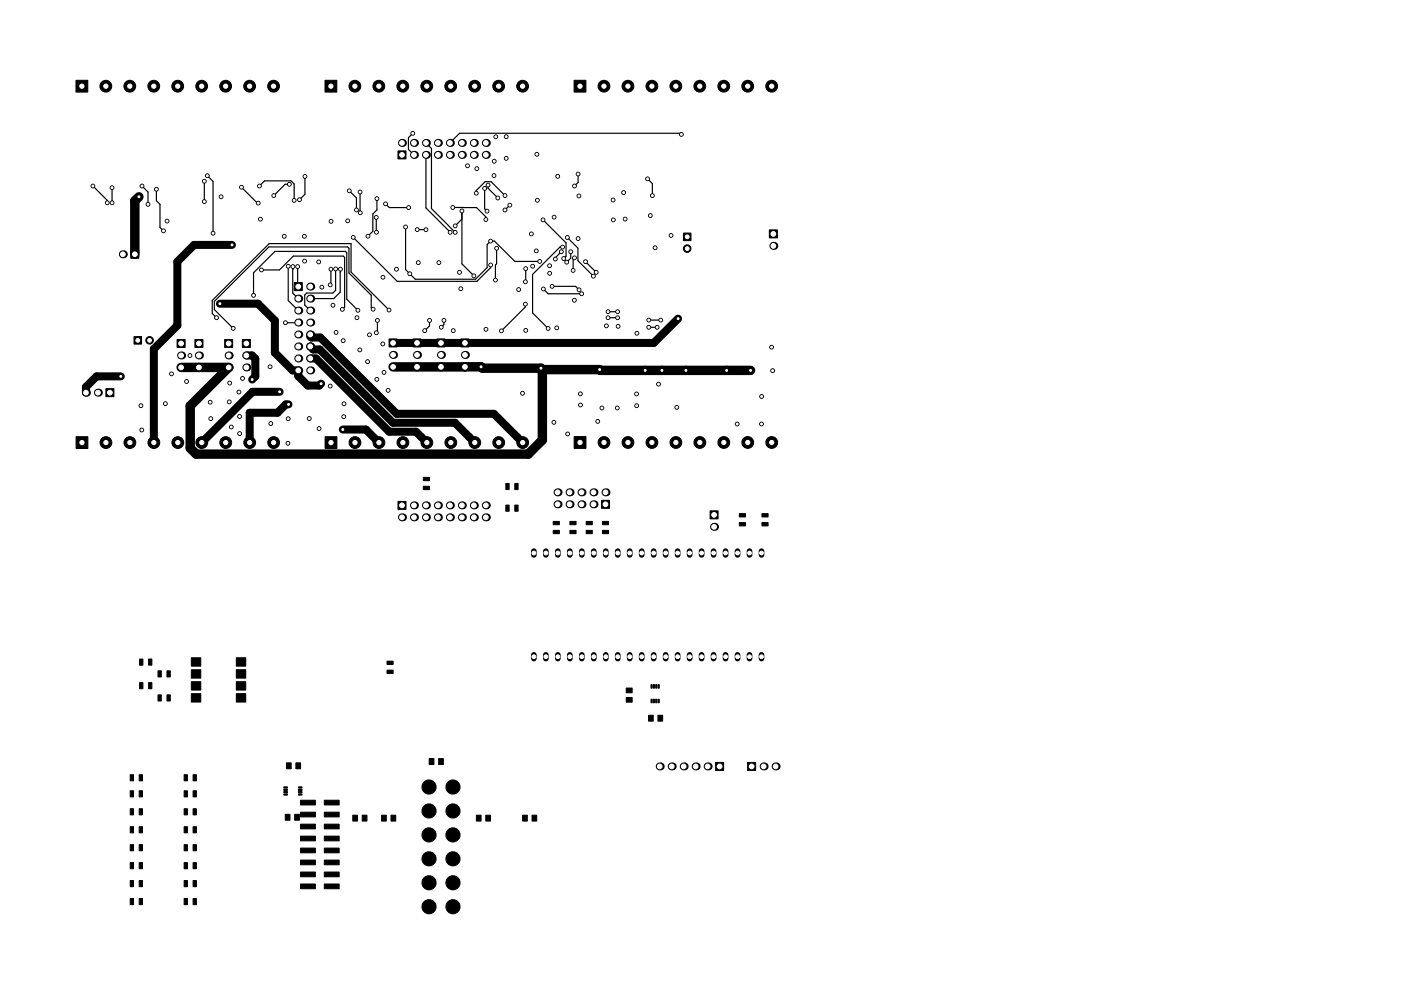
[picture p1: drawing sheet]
<svg xmlns="http://www.w3.org/2000/svg" width="297mm" height="210mm" viewBox="0 0 297 210" stroke-linecap="round" stroke-linejoin="round" font-family="sans-serif">
<g fill="none" stroke="#000" stroke-width="1.2">
<path d="M113.2 116.9v.8M115.7 116.9v.8M118.3 116.9v.8M120.8 116.9v.8M123.4 116.9v.8M125.9 116.9v.8M128.4 116.9v.8M131 116.9v.8M133.5 116.9v.8M136.1 116.9v.8M138.6 116.9v.8M141.1 116.9v.8"/>
<path d="M143.7 116.9v.8M146.2 116.9v.8M148.8 116.9v.8M151.3 116.9v.8M153.8 116.9v.8M156.4 116.9v.8M158.9 116.9v.8M161.5 116.9v.8M113.2 138.9v.8M115.7 138.9v.8M118.3 138.9v.8M120.8 138.9v.8"/>
<path d="M123.4 138.9v.8M125.9 138.9v.8M128.4 138.9v.8M131 138.9v.8M133.5 138.9v.8M136.1 138.9v.8M138.6 138.9v.8M141.1 138.9v.8M143.7 138.9v.8M146.2 138.9v.8M148.8 138.9v.8M151.3 138.9v.8"/>
<path d="M153.8 138.9v.8M156.4 138.9v.8M158.9 138.9v.8M161.5 138.9v.8"/>
</g>
<g fill="#000" stroke="#000" stroke-width=".21">
<path d="M16.1 17h2.5v2.5h-2.5zM68.9 17h2.5v2.5h-2.5zM121.7 17h2.5v2.5h-2.5zM84.4 32h1.7v1.7h-1.7zM27.7 53.1h1.7v1.7h-1.7zM144.9 49.4h1.6v1.6h-1.6zM163.1 48.8h1.7v1.7h-1.7zM28.4 71.4h1.6v1.6h-1.6zM37.5 72h1.7v1.7h-1.7zM41.3 72h1.7v1.7h-1.7zM47.6 72h1.7v1.7h-1.7zM51.4 72h1.7v1.7h-1.7z"/>
<path d="M62.4 60h1.7v1.7h-1.7zM82.5 71.9h1.7v1.7h-1.7zM87.6 71.9h1.7v1.7h-1.7zM92.6 71.9h1.7v1.7h-1.7zM97.7 71.9h1.7v1.7h-1.7zM16.1 92.6h2.5v2.5h-2.5zM22.4 82.5h1.7v1.7h-1.7zM68.9 92.6h2.5v2.5h-2.5zM121.7 92.6h2.5v2.5h-2.5zM84.4 106.4h1.7v1.7h-1.7zM89.7 101.3h1.4v.7h-1.4zM89.7 103.2h1.4v.7h-1.4z"/>
<path d="M107.2 102.6h.7v1.3h-.7zM107.2 107.2h.7v1.3h-.7zM109.1 102.6h.7v1.3h-.7zM109.1 107.2h.7v1.3h-.7zM117.3 110.6h1.3v.7h-1.3zM117.3 112.5h1.3v.7h-1.3zM120.8 112.5h1.3v.7h-1.3zM120.8 110.6h1.3v.7h-1.3zM124.3 110.6h1.3v.7h-1.3zM124.3 112.5h1.3v.7h-1.3zM127.7 110.6h1.3v.7h-1.3zM127.7 112.5h1.3v.7h-1.3z"/>
<path d="M127.5 106.1h1.7v1.7h-1.7zM150.6 108.4h1.6v1.7h-1.6zM156.8 109h1.2v.7h-1.2zM156.8 110.9h1.2v.7h-1.2zM161.6 110.9h1.3v.7h-1.3zM161.6 109h1.3v.7h-1.3zM40.6 139.6h2v1.7h-2zM50.1 139.6h2v1.7h-2zM29.6 139.8h.7v1.3h-.7zM29.6 144.8h.7v1.3h-.7zM31.5 139.8h.7v1.3h-.7zM31.5 144.8h.7v1.3h-.7z"/>
<path d="M33.5 142.3h.7v1.3h-.7zM33.5 147.4h.7v1.3h-.7zM35.4 142.3h.7v1.3h-.7zM35.4 147.4h.7v1.3h-.7zM40.6 142.1h2v1.8h-2zM40.6 144.6h2v1.8h-2zM40.6 147.2h2v1.8h-2zM50.1 147.2h2v1.8h-2zM50.1 144.6h2v1.8h-2zM50.1 142.1h2v1.8h-2zM82 140.3h1.4v.7h-1.4zM82 142.2h1.4v.7h-1.4z"/>
<path d="M132.8 146h1.2v1h-1.2zM132.8 148h1.2v1h-1.2zM137.5 151.8h1v1.2h-1zM138 148.4h.3v.7h-.3zM138 145.3h.3v.7h-.3zM138.5 148.4h.3v.7h-.3zM138.5 145.3h.3v.7h-.3zM139 148.4h.3v.7h-.3zM139 145.3h.3v.7h-.3zM139.5 151.8h1v1.2h-1zM139.5 148.4h.3v.7h-.3zM139.5 145.3h.3v.7h-.3z"/>
<path d="M27.6 164.4h.7v1.3h-.7zM27.6 175.4h.7v1.3h-.7zM27.6 171.6h.7v1.3h-.7zM27.6 167.8h.7v1.3h-.7zM27.6 179.2h.7v1.3h-.7zM29.5 164.4h.7v1.3h-.7zM29.5 175.4h.7v1.3h-.7zM29.5 171.6h.7v1.3h-.7zM29.5 167.8h.7v1.3h-.7zM29.5 179.2h.7v1.3h-.7zM39 179.2h.7v1.3h-.7zM39 171.6h.7v1.3h-.7z"/>
<path d="M39 167.8h.7v1.3h-.7zM39 164.4h.7v1.3h-.7zM39 175.4h.7v1.3h-.7zM40.9 179.2h.7v1.3h-.7zM40.9 171.6h.7v1.3h-.7zM40.9 167.8h.7v1.3h-.7zM40.9 164.4h.7v1.3h-.7zM40.9 175.4h.7v1.3h-.7zM60.2 166.9h.7v.3h-.7zM60.2 167.4h.7v.3h-.7zM60.2 167.9h.7v.3h-.7zM60.2 168.4h.7v.3h-.7z"/>
<path d="M60.5 172.8h1v1.2h-1zM60.7 161.9h1v1.2h-1zM62.5 172.8h1v1.2h-1zM62.7 161.9h1v1.2h-1zM63.3 168.4h.7v.3h-.7zM63.3 167.9h.7v.3h-.7zM63.3 167.4h.7v.3h-.7zM63.3 166.9h.7v.3h-.7zM63.7 169.8h3.2v1h-3.2zM63.7 172.3h3.2v1h-3.2zM63.7 174.9h3.2v1h-3.2zM63.7 177.4h3.2v1h-3.2z"/>
<path d="M63.7 179.9h3.2v1h-3.2zM68.8 169.8h3.1v1h-3.1zM68.8 172.3h3.1v1h-3.1zM68.8 174.9h3.1v1h-3.1zM68.8 177.4h3.1v1h-3.1zM68.8 179.9h3.1v1h-3.1zM74.8 173h1v1.2h-1zM76.8 173h1v1.2h-1zM80.9 173h1v1.2h-1zM82.9 173h1v1.2h-1zM91 161h1v1.2h-1zM93 161h1v1.2h-1z"/>
<path d="M101 173h1v1.2h-1zM103 173h1v1.2h-1zM110.8 173h1v1.2h-1zM112.8 173h1v1.2h-1zM151.7 161.8h1.7v1.7h-1.7zM158.5 161.8h1.7v1.7h-1.7zM27.6 190.6h.7v1.3h-.7zM27.6 186.8h.7v1.3h-.7zM27.6 183h.7v1.3h-.7zM29.5 190.6h.7v1.3h-.7zM29.5 186.8h.7v1.3h-.7zM29.5 183h.7v1.3h-.7z"/>
<path d="M39 190.6h.7v1.3h-.7zM39 186.8h.7v1.3h-.7zM39 183h.7v1.3h-.7zM40.9 190.6h.7v1.3h-.7zM40.9 186.8h.7v1.3h-.7zM40.9 183h.7v1.3h-.7zM63.7 182.5h3.2v1h-3.2zM63.7 185h3.2v1h-3.2zM63.7 187.6h3.2v1h-3.2zM68.8 182.5h3.1v1h-3.1zM68.8 185h3.1v1h-3.1zM68.8 187.6h3.1v1h-3.1z"/>
<circle cx="22.4" cy="18.3" r="1.25"/>
<circle cx="27.5" cy="18.3" r="1.25"/>
<circle cx="32.6" cy="18.3" r="1.25"/>
<circle cx="37.7" cy="18.3" r="1.25"/>
<circle cx="42.8" cy="18.3" r="1.25"/>
<circle cx="47.8" cy="18.3" r="1.25"/>
<circle cx="52.9" cy="18.3" r="1.25"/>
<circle cx="58" cy="18.3" r="1.25"/>
<circle cx="75.2" cy="18.3" r="1.25"/>
<circle cx="80.3" cy="18.3" r="1.25"/>
<circle cx="85.4" cy="18.3" r="1.25"/>
<circle cx="90.5" cy="18.3" r="1.25"/>
<circle cx="95.6" cy="18.3" r="1.25"/>
<circle cx="100.6" cy="18.3" r="1.25"/>
<circle cx="105.7" cy="18.3" r="1.25"/>
<circle cx="110.8" cy="18.3" r="1.25"/>
<circle cx="128.1" cy="18.3" r="1.25"/>
<circle cx="133.1" cy="18.3" r="1.25"/>
<circle cx="138.2" cy="18.3" r="1.25"/>
<circle cx="143.3" cy="18.3" r="1.25"/>
<circle cx="148.4" cy="18.3" r="1.25"/>
<circle cx="153.5" cy="18.3" r="1.25"/>
<circle cx="158.5" cy="18.3" r="1.25"/>
<circle cx="163.6" cy="18.3" r="1.25"/>
<circle cx="19.7" cy="39.5" r=".4"/>
<circle cx="23.8" cy="39.8" r=".4"/>
<circle cx="30.1" cy="39.5" r=".4"/>
<circle cx="43.3" cy="38.5" r=".4"/>
<circle cx="44" cy="37.3" r=".4"/>
<circle cx="51.2" cy="39.7" r=".4"/>
<circle cx="55" cy="39.5" r=".4"/>
<circle cx="61.4" cy="39.1" r=".4"/>
<circle cx="64.7" cy="37.4" r=".4"/>
<circle cx="87.5" cy="28.3" r=".4"/>
<circle cx="99.1" cy="35.2" r=".4"/>
<circle cx="101.1" cy="35.8" r=".4"/>
<circle cx="102.8" cy="40" r=".4"/>
<circle cx="103.5" cy="39.3" r=".4"/>
<circle cx="104.7" cy="37.3" r=".4"/>
<circle cx="104.8" cy="34.2" r=".4"/>
<circle cx="105.1" cy="29" r=".4"/>
<circle cx="107.3" cy="33.6" r=".4"/>
<circle cx="107.3" cy="29" r=".4"/>
<circle cx="113.8" cy="32.7" r=".4"/>
<circle cx="118.2" cy="37.4" r=".4"/>
<circle cx="121.8" cy="39.5" r=".4"/>
<circle cx="122.6" cy="36.9" r=".4"/>
<circle cx="137.3" cy="37.9" r=".4"/>
<circle cx="144.5" cy="28.5" r=".4"/>
<circle cx="22.7" cy="43" r=".4"/>
<circle cx="23.8" cy="43" r=".4"/>
<circle cx="29.5" cy="41.8" r=".4"/>
<circle cx="31.4" cy="43.4" r=".4"/>
<circle cx="33.2" cy="40.2" r=".4"/>
<circle cx="34.7" cy="49" r=".4"/>
<circle cx="35.4" cy="46.9" r=".4"/>
<circle cx="43.3" cy="42.8" r=".4"/>
<circle cx="45.2" cy="49.5" r=".4"/>
<circle cx="46.9" cy="41.8" r=".4"/>
<circle cx="49.2" cy="52" r=".4"/>
<circle cx="54.7" cy="43.1" r=".4"/>
<circle cx="55.2" cy="46.5" r=".4"/>
<circle cx="55.4" cy="57.3" r=".4"/>
<circle cx="58.1" cy="41.5" r=".4"/>
<circle cx="60.3" cy="50.1" r=".4"/>
<circle cx="61.1" cy="56.5" r=".4"/>
<circle cx="62.1" cy="56.6" r=".4"/>
<circle cx="62.4" cy="42.5" r=".4"/>
<circle cx="63.1" cy="56.6" r=".4"/>
<circle cx="63.5" cy="42.4" r=".4"/>
<circle cx="64.5" cy="50.1" r=".4"/>
<circle cx="64.6" cy="55.4" r=".4"/>
<circle cx="67.6" cy="55.6" r=".4"/>
<circle cx="70.2" cy="57.1" r=".4"/>
<circle cx="70.2" cy="47" r=".4"/>
<circle cx="71.2" cy="57.1" r=".4"/>
<circle cx="72.2" cy="57.1" r=".4"/>
<circle cx="73.7" cy="46.9" r=".4"/>
<circle cx="74.1" cy="40.5" r=".4"/>
<circle cx="74.9" cy="50.4" r=".4"/>
<circle cx="75.6" cy="44.5" r=".4"/>
<circle cx="76.3" cy="40.7" r=".4"/>
<circle cx="76.4" cy="45.1" r=".4"/>
<circle cx="78" cy="50.1" r=".4"/>
<circle cx="79.8" cy="46.1" r=".4"/>
<circle cx="79.8" cy="49.3" r=".4"/>
<circle cx="79.9" cy="42.1" r=".4"/>
<circle cx="81.2" cy="58.8" r=".4"/>
<circle cx="81.7" cy="43.3" r=".4"/>
<circle cx="84.1" cy="57.1" r=".4"/>
<circle cx="86" cy="48.2" r=".4"/>
<circle cx="86.6" cy="44" r=".4"/>
<circle cx="86.9" cy="58.1" r=".4"/>
<circle cx="88.5" cy="48.7" r=".4"/>
<circle cx="88.7" cy="55.7" r=".4"/>
<circle cx="90.3" cy="48.7" r=".4"/>
<circle cx="93.1" cy="55.7" r=".4"/>
<circle cx="95.4" cy="49.3" r=".4"/>
<circle cx="96" cy="44" r=".4"/>
<circle cx="96.5" cy="49.3" r=".4"/>
<circle cx="96.5" cy="47.9" r=".4"/>
<circle cx="97.4" cy="57.8" r=".4"/>
<circle cx="97.9" cy="44.7" r=".4"/>
<circle cx="100.5" cy="58.5" r=".4"/>
<circle cx="101" cy="41" r=".4"/>
<circle cx="103" cy="46.6" r=".4"/>
<circle cx="103.3" cy="44.8" r=".4"/>
<circle cx="104" cy="51.2" r=".4"/>
<circle cx="104" cy="56.2" r=".4"/>
<circle cx="105" cy="59.4" r=".4"/>
<circle cx="105.3" cy="52.7" r=".4"/>
<circle cx="105.5" cy="42" r=".4"/>
<circle cx="107.1" cy="44.6" r=".4"/>
<circle cx="107.1" cy="41.5" r=".4"/>
<circle cx="108.1" cy="43.5" r=".4"/>
<circle cx="111.4" cy="59.8" r=".4"/>
<circle cx="111.5" cy="57" r=".4"/>
<circle cx="112.7" cy="49.6" r=".4"/>
<circle cx="112.9" cy="56.5" r=".4"/>
<circle cx="113.7" cy="53.2" r=".4"/>
<circle cx="113.9" cy="42.5" r=".4"/>
<circle cx="114.4" cy="55.5" r=".4"/>
<circle cx="115.1" cy="46.6" r=".4"/>
<circle cx="116.5" cy="56.4" r=".4"/>
<circle cx="116.5" cy="58" r=".4"/>
<circle cx="117.5" cy="46.1" r=".4"/>
<circle cx="117.7" cy="55" r=".4"/>
<circle cx="119" cy="53.4" r=".4"/>
<circle cx="119.3" cy="52.4" r=".4"/>
<circle cx="119.5" cy="54.9" r=".4"/>
<circle cx="120.2" cy="55.6" r=".4"/>
<circle cx="120.3" cy="50.4" r=".4"/>
<circle cx="121" cy="53.4" r=".4"/>
<circle cx="121.5" cy="57.4" r=".4"/>
<circle cx="121.8" cy="54.7" r=".4"/>
<circle cx="122.6" cy="50.6" r=".4"/>
<circle cx="122.7" cy="41.6" r=".4"/>
<circle cx="124.1" cy="55.5" r=".4"/>
<circle cx="125.8" cy="58.6" r=".4"/>
<circle cx="126.4" cy="57.8" r=".4"/>
<circle cx="130" cy="42.4" r=".4"/>
<circle cx="130" cy="46.7" r=".4"/>
<circle cx="132.2" cy="40.9" r=".4"/>
<circle cx="132.5" cy="46.5" r=".4"/>
<circle cx="137.9" cy="45.7" r=".4"/>
<circle cx="138.3" cy="41.5" r=".4"/>
<circle cx="138.9" cy="52.6" r=".4"/>
<circle cx="142.3" cy="50" r=".4"/>
<circle cx="145.7" cy="52.7" r=".8"/>
<circle cx="25.6" cy="79.9" r=".4"/>
<circle cx="31.7" cy="72.2" r=".8"/>
<circle cx="36.4" cy="79.3" r=".4"/>
<circle cx="40.3" cy="75.4" r=".4"/>
<circle cx="45.9" cy="67.4" r=".4"/>
<circle cx="46.6" cy="64.4" r=".4"/>
<circle cx="49.4" cy="69.7" r=".4"/>
<circle cx="53.8" cy="62.7" r=".4"/>
<circle cx="57.3" cy="77.8" r=".4"/>
<circle cx="60.5" cy="68.5" r=".4"/>
<circle cx="68.2" cy="60.9" r=".4"/>
<circle cx="70" cy="60.4" r=".4"/>
<circle cx="70.6" cy="64.8" r=".4"/>
<circle cx="71.3" cy="70.5" r=".4"/>
<circle cx="72.6" cy="65.6" r=".4"/>
<circle cx="72.8" cy="72.3" r=".4"/>
<circle cx="75.7" cy="67.4" r=".4"/>
<circle cx="75.9" cy="65.8" r=".4"/>
<circle cx="76.3" cy="74.2" r=".4"/>
<circle cx="77.9" cy="76.7" r=".4"/>
<circle cx="78.3" cy="71" r=".4"/>
<circle cx="79.1" cy="65.6" r=".4"/>
<circle cx="79.8" cy="70.6" r=".4"/>
<circle cx="80" cy="68" r=".4"/>
<circle cx="81.2" cy="73" r=".4"/>
<circle cx="81.4" cy="79" r=".4"/>
<circle cx="82.5" cy="65.8" r=".4"/>
<circle cx="90.1" cy="70.2" r=".4"/>
<circle cx="91.1" cy="68" r=".4"/>
<circle cx="93.6" cy="69.4" r=".4"/>
<circle cx="94.1" cy="68" r=".4"/>
<circle cx="96.1" cy="70.1" r=".4"/>
<circle cx="97.7" cy="61.3" r=".4"/>
<circle cx="102" cy="77.8" r=".4"/>
<circle cx="103" cy="69.9" r=".4"/>
<circle cx="106.3" cy="70.2" r=".4"/>
<circle cx="110" cy="61.4" r=".4"/>
<circle cx="111.4" cy="64.5" r=".4"/>
<circle cx="111.5" cy="70.1" r=".4"/>
<circle cx="114.7" cy="78.1" r=".4"/>
<circle cx="115.2" cy="61.3" r=".4"/>
<circle cx="116.2" cy="69.7" r=".4"/>
<circle cx="117.1" cy="60.8" r=".4"/>
<circle cx="118" cy="69.6" r=".4"/>
<circle cx="121.8" cy="63.7" r=".4"/>
<circle cx="122.8" cy="61.5" r=".4"/>
<circle cx="123.3" cy="62.3" r=".4"/>
<circle cx="127.1" cy="78.4" r=".4"/>
<circle cx="128.6" cy="69.1" r=".4"/>
<circle cx="128.9" cy="67.4" r=".4"/>
<circle cx="128.9" cy="66.1" r=".4"/>
<circle cx="130.9" cy="66.1" r=".4"/>
<circle cx="130.9" cy="67.4" r=".4"/>
<circle cx="131" cy="69.2" r=".4"/>
<circle cx="135" cy="70.7" r=".4"/>
<circle cx="136.8" cy="78.6" r=".4"/>
<circle cx="137.6" cy="69.4" r=".4"/>
<circle cx="137.6" cy="67.9" r=".4"/>
<circle cx="139.3" cy="69.4" r=".4"/>
<circle cx="140.1" cy="67.9" r=".4"/>
<circle cx="140.3" cy="78.6" r=".4"/>
<circle cx="143.8" cy="67.6" r=".4"/>
<circle cx="145.4" cy="78.6" r=".4"/>
<circle cx="154.1" cy="78.6" r=".4"/>
<circle cx="159.1" cy="78.6" r=".4"/>
<circle cx="163.6" cy="73.7" r=".4"/>
<circle cx="163.8" cy="78.6" r=".4"/>
<circle cx="22.5" cy="93.9" r="1.25"/>
<circle cx="27.5" cy="93.9" r="1.25"/>
<circle cx="29.9" cy="86.1" r=".4"/>
<circle cx="30.1" cy="91.2" r=".4"/>
<circle cx="32.6" cy="93.9" r="1.25"/>
<circle cx="35.1" cy="85.6" r=".4"/>
<circle cx="37.7" cy="93.9" r="1.25"/>
<circle cx="39.6" cy="80.9" r=".4"/>
<circle cx="42.8" cy="93.9" r="1.25"/>
<circle cx="44.6" cy="85.3" r=".4"/>
<circle cx="44.7" cy="88.8" r=".4"/>
<circle cx="47.9" cy="93.9" r="1.25"/>
<circle cx="48.6" cy="85.3" r=".4"/>
<circle cx="48.7" cy="81.3" r=".4"/>
<circle cx="49" cy="90.6" r=".4"/>
<circle cx="50.7" cy="83.2" r=".4"/>
<circle cx="50.8" cy="88.4" r=".4"/>
<circle cx="50.8" cy="92" r=".4"/>
<circle cx="51.4" cy="80.3" r=".4"/>
<circle cx="52.9" cy="93.9" r="1.25"/>
<circle cx="53.5" cy="80.5" r=".4"/>
<circle cx="57.4" cy="89.9" r=".4"/>
<circle cx="58" cy="93.9" r="1.25"/>
<circle cx="59.3" cy="83.1" r=".4"/>
<circle cx="61" cy="94.1" r=".4"/>
<circle cx="61.1" cy="88.8" r=".4"/>
<circle cx="61.2" cy="85.8" r=".4"/>
<circle cx="65.6" cy="88.8" r=".4"/>
<circle cx="67.7" cy="90.9" r=".4"/>
<circle cx="68.1" cy="81.4" r=".4"/>
<circle cx="70" cy="81.9" r=".4"/>
<circle cx="72.7" cy="91.1" r=".4"/>
<circle cx="72.9" cy="88.4" r=".4"/>
<circle cx="72.9" cy="85.7" r=".4"/>
<circle cx="75.3" cy="93.9" r="1.25"/>
<circle cx="79.9" cy="80.5" r=".4"/>
<circle cx="80.3" cy="93.9" r="1.25"/>
<circle cx="82.3" cy="82.8" r=".4"/>
<circle cx="85.4" cy="93.9" r="1.25"/>
<circle cx="90.5" cy="93.9" r="1.25"/>
<circle cx="95.6" cy="93.9" r="1.25"/>
<circle cx="100.7" cy="93.9" r="1.25"/>
<circle cx="105.7" cy="93.9" r="1.25"/>
<circle cx="110.8" cy="83.4" r=".4"/>
<circle cx="110.8" cy="93.9" r="1.25"/>
<circle cx="117.4" cy="89.6" r=".4"/>
<circle cx="120.4" cy="92.1" r=".4"/>
<circle cx="123" cy="83.6" r=".4"/>
<circle cx="123.1" cy="85.9" r=".4"/>
<circle cx="126.7" cy="89.4" r=".4"/>
<circle cx="127.6" cy="86.6" r=".4"/>
<circle cx="128.1" cy="93.9" r="1.25"/>
<circle cx="130.9" cy="86.6" r=".4"/>
<circle cx="133.1" cy="93.9" r="1.25"/>
<circle cx="135" cy="83.6" r=".4"/>
<circle cx="135" cy="86.1" r=".4"/>
<circle cx="138.2" cy="93.9" r="1.25"/>
<circle cx="139.6" cy="81.5" r=".4"/>
<circle cx="143.3" cy="93.9" r="1.25"/>
<circle cx="143.5" cy="86.4" r=".4"/>
<circle cx="148.4" cy="93.9" r="1.25"/>
<circle cx="153.5" cy="93.9" r="1.25"/>
<circle cx="156.3" cy="90" r=".4"/>
<circle cx="158.5" cy="93.9" r="1.25"/>
<circle cx="161.5" cy="90" r=".4"/>
<circle cx="161.5" cy="84.1" r=".4"/>
<circle cx="163.6" cy="93.9" r="1.25"/>
<circle cx="91" cy="177.1" r="1.5"/>
<circle cx="91" cy="172.1" r="1.5"/>
<circle cx="91" cy="167" r="1.5"/>
<circle cx="96" cy="172.1" r="1.5"/>
<circle cx="96" cy="177.1" r="1.5"/>
<circle cx="96" cy="167" r="1.5"/>
<circle cx="91" cy="182.2" r="1.5"/>
<circle cx="91" cy="192.4" r="1.5"/>
<circle cx="91" cy="187.3" r="1.5"/>
<circle cx="96" cy="182.2" r="1.5"/>
<circle cx="96" cy="192.4" r="1.5"/>
<circle cx="96" cy="187.3" r="1.5"/>
</g>
<g fill="#000">
<circle cx="85.2" cy="30.3" r=".85"/>
<circle cx="87.8" cy="30.3" r=".85"/>
<circle cx="87.8" cy="32.9" r=".85"/>
<circle cx="90.3" cy="30.3" r=".85"/>
<circle cx="90.3" cy="32.9" r=".85"/>
<circle cx="92.8" cy="30.3" r=".85"/>
<circle cx="92.8" cy="32.9" r=".85"/>
<circle cx="95.4" cy="32.9" r=".85"/>
<circle cx="95.4" cy="30.3" r=".85"/>
<circle cx="97.9" cy="32.9" r=".85"/>
<circle cx="97.9" cy="30.3" r=".85"/>
<circle cx="100.5" cy="32.9" r=".85"/>
<circle cx="100.5" cy="30.3" r=".85"/>
<circle cx="103" cy="30.3" r=".85"/>
<circle cx="103" cy="32.9" r=".85"/>
<circle cx="26" cy="53.9" r=".85"/>
<circle cx="164" cy="52.2" r=".85"/>
<circle cx="38.4" cy="75.4" r=".85"/>
<circle cx="38.4" cy="78" r=".85"/>
<circle cx="42.2" cy="75.4" r=".85"/>
<circle cx="42.2" cy="78" r=".85"/>
<circle cx="48.5" cy="75.4" r=".85"/>
<circle cx="48.5" cy="78" r=".85"/>
<circle cx="52.2" cy="75.4" r=".85"/>
<circle cx="52.2" cy="78" r=".85"/>
<circle cx="63.2" cy="71" r=".85"/>
<circle cx="63.2" cy="65.9" r=".85"/>
<circle cx="63.2" cy="68.4" r=".85"/>
<circle cx="63.2" cy="73.5" r=".85"/>
<circle cx="63.2" cy="78.6" r=".85"/>
<circle cx="63.2" cy="76" r=".85"/>
<circle cx="63.2" cy="63.3" r=".85"/>
<circle cx="65.8" cy="71" r=".85"/>
<circle cx="65.8" cy="73.5" r=".85"/>
<circle cx="65.8" cy="60.8" r=".85"/>
<circle cx="65.8" cy="63.3" r=".85"/>
<circle cx="65.8" cy="68.4" r=".85"/>
<circle cx="65.8" cy="78.6" r=".85"/>
<circle cx="65.8" cy="65.9" r=".85"/>
<circle cx="65.8" cy="76" r=".85"/>
<circle cx="83.3" cy="75.3" r=".85"/>
<circle cx="83.3" cy="77.8" r=".85"/>
<circle cx="88.4" cy="75.3" r=".85"/>
<circle cx="88.4" cy="77.8" r=".85"/>
<circle cx="93.5" cy="77.8" r=".85"/>
<circle cx="93.5" cy="75.3" r=".85"/>
<circle cx="98.6" cy="77.8" r=".85"/>
<circle cx="98.6" cy="75.3" r=".85"/>
<circle cx="18.2" cy="83.3" r=".85"/>
<circle cx="20.8" cy="83.3" r=".85"/>
<circle cx="85.2" cy="109.8" r=".85"/>
<circle cx="87.8" cy="109.8" r=".85"/>
<circle cx="87.8" cy="107.2" r=".85"/>
<circle cx="90.3" cy="109.8" r=".85"/>
<circle cx="90.3" cy="107.2" r=".85"/>
<circle cx="92.8" cy="109.8" r=".85"/>
<circle cx="92.8" cy="107.2" r=".85"/>
<circle cx="95.4" cy="109.8" r=".85"/>
<circle cx="95.4" cy="107.2" r=".85"/>
<circle cx="97.9" cy="109.8" r=".85"/>
<circle cx="97.9" cy="107.2" r=".85"/>
<circle cx="100.5" cy="107.2" r=".85"/>
<circle cx="100.5" cy="109.8" r=".85"/>
<circle cx="103" cy="109.8" r=".85"/>
<circle cx="103" cy="107.2" r=".85"/>
<circle cx="118.2" cy="107" r=".85"/>
<circle cx="118.2" cy="104.5" r=".85"/>
<circle cx="120.8" cy="104.5" r=".85"/>
<circle cx="120.8" cy="107" r=".85"/>
<circle cx="123.3" cy="104.5" r=".85"/>
<circle cx="123.3" cy="107" r=".85"/>
<circle cx="125.8" cy="107" r=".85"/>
<circle cx="125.8" cy="104.5" r=".85"/>
<circle cx="128.4" cy="104.5" r=".85"/>
<circle cx="151.4" cy="111.8" r=".85"/>
<circle cx="139.9" cy="162.6" r=".85"/>
<circle cx="142.4" cy="162.6" r=".85"/>
<circle cx="145" cy="162.6" r=".85"/>
<circle cx="147.5" cy="162.6" r=".85"/>
<circle cx="150" cy="162.6" r=".85"/>
<circle cx="161.9" cy="162.6" r=".85"/>
<circle cx="164.4" cy="162.6" r=".85"/>
</g>
<path d="M29.5 41.8l-.9 .8v11.3M38.4 78h10.1l-8.2 8.1v9l1.3 1.2h70.4l3-2.9v-15M83.3 77.8h18.7l.3 .3h12.4l.3 .3M115 78.4h12.1l.2 .2h31.8" fill="none" stroke="#000" stroke-width="2"/>
<g fill="none" stroke="#000" stroke-width=".25">
<path d="M19.7 39.5l3 3v.5M23.8 39.8v3.2M30.1 39.5l1.3 1.2v2.7M43.3 38.5v4.3M44 37.3l1.2 1.2v11M51.2 39.7l3.4 3.4h.1M55 39.5l1.1-1.1h5.6l.7 .6v3.5M61.4 39.1h-.9l-2.5 2.4M64.7 37.4v3.8l-1.2 1.2M87.5 28.3l-.9 .9v2.5l1.2 1.2M90.3 30.3l1.2 1.2v12.8l5 5M90.3 32.9v11.2l5.1 5.2"/>
<path d="M102.8 40v4.3l.5 .5M103.5 39.3v.6l2 2.1M122.6 36.9v1.8l-.8 .8M137.3 37.9l1 1.1v2.5M144.5 28.5l-.3-.2h-46.8l-2 2M33.2 40.2v2.4l.7 .8v4.8l.8 .8M55.4 57.3h3.9l2.9-3h10.6l.3 .3v10.5l-.5 .5M61.1 56.5v7.3l2.1 2.1M62.1 56.6v5.6l1.1 1.1M63.1 56.6v4.1l.1 .1M70.2 57.1v3.2l-.2 .1M71.2 57.1v4.5l-.6 .6h-5.6l-.4 .4v2.1l1.2 1.2"/>
<path d="M72.2 57.1l-.1 4.9-1.3 1.3h-5M74.1 40.5l1.5 1.5v2.5M74.9 50.4l9.3 9.3h16.9l2.9-2.9v-.6M76.3 40.7l.1 4.4M79.8 46.1v3.2M79.9 42.1v2.4l-.9 .9v3.7l-1 1M81.7 43.3l.8 .7h4.1M86 48.2v9l2 2h12.8l2.5-2.4v-4.9l.7-.7h.8l4.4 4.3h5.2M88.5 48.7h1.8M95.1 47.8v.1M96 44h5l2 2v.6M97.9 46.5l-1.4 1.4"/>
<path d="M97.9 44.7v11.3l2.6 2.5M98.3 44h.1M101 41v-.6l1.9-1.9h1.2l3 3M105.3 52.7v3.3l-.3 .2v3.2M108.1 43.5l-1 1.1M111.5 57l-.1 2.8M115.1 46.6l4.9 4.9v2.9l-.5 .5M119 53.4l-1.3 1.3v.3M119.3 52.4h-.6l-5.8 5.8v8.2l3.3 3.3M120.3 50.4l2.2 2.2v2.7l3.3 3.3M121 53.4v1.4l-.8 .8M121.8 54.7l-.3 .3v2.4"/>
<path d="M124.1 55.5l2.3 2.3M53.8 62.7v-4.8l4.5-4.6h15l.2 .3v9.9l2.4 2.3M63.2 68.4l-2.7 .1M79.1 65.6l-.4-.4v-2.6l-4.7-4.7v-5.2l-.3-.3h-16.7l-11.6 11.5v1.8l4 4M80 68v2.4l-.2 .2M82.5 65.8l-8.1-8.1v-6h-17.3l-12.1 12.1v2.7l.9 .9M91.1 68v1.1l-1 1.1M94.1 68v.9l-.5 .5M111.4 64.5v.6l-5.1 5.1M115.2 61.3l1 1h7.1M117.1 60.8h4.9l.8 .7M128.9 66.1h2"/>
<path d="M128.9 67.4h2M137.6 67.9h2.5M137.6 69.4h1.7"/>
</g>
<path d="M49.2 52h-8l-3.6 3.5v13.6l-5 4.9v19.9M25.6 79.9h-5.1l-2.3 2.2v1.2M46.6 64.4h8.1l3.6 3.6v6.8l3.7 3.8h1.2v1.2l2.1 2h2.4l.4-.4M52.2 75.4h1.2l.7 .7v3.8l-.6 .6M65.8 76h1.2l15.5 15.6h5.7l2.3 2.3M65.8 71v.4l.2 .2h1.9l16.2 16.2h20.6l6.1 6.1M65.8 73.5h.1M65.8 73.5l.6 .6h1.4l15.5 15.6h13.2l4.2 4.2M143.8 67.6l-5.2 5.2h-55.3M59.3 83.1h-5.8l-10.7 10.8M61.2 85.8h-.6l-1.8 1.8h-5.9v6.3M72.7 91.1h4.9l2.7 2.8" fill="none" stroke="#000" stroke-width="1.7"/>
<g fill="#fff" stroke="#fff" stroke-width=".21">
<circle cx="29.5" cy="41.8" r=".2"/>
<circle cx="97.4" cy="57.8" r=".2"/>
<circle cx="97.7" cy="61.3" r=".2"/>
<circle cx="110" cy="61.4" r=".2"/>
<circle cx="111.5" cy="70.1" r=".2"/>
<circle cx="103" cy="69.9" r=".2"/>
<circle cx="96.1" cy="70.1" r=".2"/>
<circle cx="70" cy="81.9" r=".2"/>
<circle cx="72.9" cy="85.7" r=".2"/>
<circle cx="72.9" cy="88.4" r=".2"/>
<circle cx="61.1" cy="88.8" r=".2"/>
<circle cx="57.3" cy="77.8" r=".2"/>
<circle cx="67.7" cy="90.9" r=".2"/>
<circle cx="65.6" cy="88.8" r=".2"/>
<circle cx="61" cy="94.1" r=".2"/>
<circle cx="57.4" cy="89.9" r=".2"/>
<circle cx="79.9" cy="80.5" r=".2"/>
<circle cx="82.3" cy="82.8" r=".2"/>
<circle cx="68.2" cy="60.9" r=".2"/>
<circle cx="67.6" cy="55.6" r=".2"/>
<circle cx="64.6" cy="55.4" r=".2"/>
<circle cx="70.2" cy="47" r=".2"/>
<circle cx="73.7" cy="46.9" r=".2"/>
<circle cx="46.9" cy="41.8" r=".2"/>
<circle cx="35.4" cy="46.9" r=".2"/>
<circle cx="55.2" cy="46.5" r=".2"/>
<circle cx="60.3" cy="50.1" r=".2"/>
<circle cx="64.5" cy="50.1" r=".2"/>
<circle cx="101.1" cy="35.8" r=".2"/>
<circle cx="99.1" cy="35.2" r=".2"/>
<circle cx="105.1" cy="29" r=".2"/>
<circle cx="107.3" cy="29" r=".2"/>
<circle cx="107.3" cy="33.6" r=".2"/>
<circle cx="104.8" cy="34.2" r=".2"/>
<circle cx="104.7" cy="37.3" r=".2"/>
<circle cx="137.9" cy="45.7" r=".2"/>
<circle cx="138.9" cy="52.6" r=".2"/>
<circle cx="142.3" cy="50" r=".2"/>
<circle cx="132.2" cy="40.9" r=".2"/>
<circle cx="132.5" cy="46.5" r=".2"/>
<circle cx="118.2" cy="37.4" r=".2"/>
<circle cx="113.8" cy="32.7" r=".2"/>
<circle cx="113.9" cy="42.5" r=".2"/>
<circle cx="117.5" cy="46.1" r=".2"/>
<circle cx="122.7" cy="41.6" r=".2"/>
<circle cx="130" cy="42.4" r=".2"/>
<circle cx="130" cy="46.7" r=".2"/>
<circle cx="122.6" cy="50.6" r=".2"/>
<circle cx="123.1" cy="85.9" r=".2"/>
<circle cx="123" cy="83.6" r=".2"/>
<circle cx="130.9" cy="86.6" r=".2"/>
<circle cx="127.6" cy="86.6" r=".2"/>
<circle cx="110.8" cy="83.4" r=".2"/>
<circle cx="117.4" cy="89.6" r=".2"/>
<circle cx="126.7" cy="89.4" r=".2"/>
<circle cx="120.4" cy="92.1" r=".2"/>
<circle cx="161.5" cy="90" r=".2"/>
<circle cx="156.3" cy="90" r=".2"/>
<circle cx="161.5" cy="84.1" r=".2"/>
<circle cx="163.8" cy="78.6" r=".2"/>
<circle cx="163.6" cy="73.7" r=".2"/>
<circle cx="139.6" cy="81.5" r=".2"/>
<circle cx="143.5" cy="86.4" r=".2"/>
<circle cx="135" cy="83.6" r=".2"/>
<circle cx="135" cy="86.1" r=".2"/>
<circle cx="135" cy="70.7" r=".2"/>
<circle cx="131" cy="69.2" r=".2"/>
<circle cx="128.6" cy="69.1" r=".2"/>
<circle cx="118" cy="69.6" r=".2"/>
<circle cx="121.8" cy="63.7" r=".2"/>
<circle cx="113.7" cy="53.2" r=".2"/>
<circle cx="112.9" cy="56.5" r=".2"/>
<circle cx="116.5" cy="58" r=".2"/>
<circle cx="116.5" cy="56.4" r=".2"/>
<circle cx="93.1" cy="55.7" r=".2"/>
<circle cx="88.7" cy="55.7" r=".2"/>
<circle cx="84.1" cy="57.1" r=".2"/>
<circle cx="81.2" cy="58.8" r=".2"/>
<circle cx="77.9" cy="76.7" r=".2"/>
<circle cx="81.2" cy="73" r=".2"/>
<circle cx="81.4" cy="79" r=".2"/>
<circle cx="76.3" cy="74.2" r=".2"/>
<circle cx="72.8" cy="72.3" r=".2"/>
<circle cx="71.3" cy="70.5" r=".2"/>
<circle cx="78.3" cy="71" r=".2"/>
<circle cx="75.7" cy="67.4" r=".2"/>
<circle cx="70.6" cy="64.8" r=".2"/>
<circle cx="29.9" cy="86.1" r=".2"/>
<circle cx="30.1" cy="91.2" r=".2"/>
<circle cx="35.1" cy="85.6" r=".2"/>
<circle cx="36.4" cy="79.3" r=".2"/>
<circle cx="39.6" cy="80.9" r=".2"/>
<circle cx="40.3" cy="75.4" r=".2"/>
<circle cx="49" cy="90.6" r=".2"/>
<circle cx="50.8" cy="92" r=".2"/>
<circle cx="50.8" cy="88.4" r=".2"/>
<circle cx="51.4" cy="80.3" r=".2"/>
<circle cx="50.7" cy="83.2" r=".2"/>
<circle cx="48.7" cy="81.3" r=".2"/>
<circle cx="48.6" cy="85.3" r=".2"/>
<circle cx="44.7" cy="88.8" r=".2"/>
<circle cx="44.6" cy="85.3" r=".2"/>
<circle cx="112.7" cy="49.6" r=".2"/>
<circle cx="102" cy="77.8" r=".2"/>
<circle cx="114.7" cy="78.1" r=".2"/>
<circle cx="127.1" cy="78.4" r=".2"/>
<circle cx="159.1" cy="78.6" r=".2"/>
<circle cx="154.1" cy="78.6" r=".2"/>
<circle cx="145.4" cy="78.6" r=".2"/>
<circle cx="140.3" cy="78.6" r=".2"/>
<circle cx="136.8" cy="78.6" r=".2"/>
<circle cx="138.3" cy="41.5" r=".2"/>
<circle cx="137.3" cy="37.9" r=".2"/>
<circle cx="87.5" cy="28.3" r=".2"/>
<circle cx="59.3" cy="83.1" r=".2"/>
<circle cx="61.2" cy="85.8" r=".2"/>
<circle cx="68.1" cy="81.4" r=".2"/>
<circle cx="96.5" cy="47.9" r=".2"/>
<circle cx="90.3" cy="48.7" r=".2"/>
<circle cx="88.5" cy="48.7" r=".2"/>
<circle cx="144.5" cy="28.5" r=".2"/>
<circle cx="74.9" cy="50.4" r=".2"/>
<circle cx="117.1" cy="60.8" r=".2"/>
<circle cx="143.8" cy="67.6" r=".2"/>
<circle cx="25.6" cy="79.9" r=".2"/>
<circle cx="49.2" cy="52" r=".2"/>
<circle cx="55.4" cy="57.3" r=".2"/>
<circle cx="72.6" cy="65.6" r=".2"/>
<circle cx="91.1" cy="68" r=".2"/>
<circle cx="90.1" cy="70.2" r=".2"/>
<circle cx="53.8" cy="62.7" r=".2"/>
<circle cx="75.9" cy="65.8" r=".2"/>
<circle cx="49.4" cy="69.7" r=".2"/>
<circle cx="79.1" cy="65.6" r=".2"/>
<circle cx="46.6" cy="64.4" r=".2"/>
<circle cx="45.9" cy="67.4" r=".2"/>
<circle cx="82.5" cy="65.8" r=".2"/>
<circle cx="86.9" cy="58.1" r=".2"/>
<circle cx="86" cy="48.2" r=".2"/>
<circle cx="114.4" cy="55.5" r=".2"/>
<circle cx="104" cy="51.2" r=".2"/>
<circle cx="119" cy="53.4" r=".2"/>
<circle cx="117.7" cy="55" r=".2"/>
<circle cx="93.6" cy="69.4" r=".2"/>
<circle cx="94.1" cy="68" r=".2"/>
<circle cx="79.8" cy="70.6" r=".2"/>
<circle cx="80" cy="68" r=".2"/>
<circle cx="72.7" cy="91.1" r=".2"/>
<circle cx="100.5" cy="58.5" r=".2"/>
<circle cx="97.9" cy="44.7" r=".2"/>
<circle cx="96" cy="44" r=".2"/>
<circle cx="103" cy="46.6" r=".2"/>
<circle cx="72.2" cy="57.1" r=".2"/>
<circle cx="79.8" cy="49.3" r=".2"/>
<circle cx="79.8" cy="46.1" r=".2"/>
<circle cx="76.4" cy="45.1" r=".2"/>
<circle cx="76.3" cy="40.7" r=".2"/>
<circle cx="63.5" cy="42.4" r=".2"/>
<circle cx="64.7" cy="37.4" r=".2"/>
<circle cx="60.5" cy="68.5" r=".2"/>
<circle cx="62.4" cy="42.5" r=".2"/>
<circle cx="55" cy="39.5" r=".2"/>
<circle cx="22.7" cy="43" r=".2"/>
<circle cx="19.7" cy="39.5" r=".2"/>
<circle cx="63.1" cy="56.6" r=".2"/>
<circle cx="23.8" cy="43" r=".2"/>
<circle cx="23.8" cy="39.8" r=".2"/>
<circle cx="61.1" cy="56.5" r=".2"/>
<circle cx="45.2" cy="49.5" r=".2"/>
<circle cx="44" cy="37.3" r=".2"/>
<circle cx="70" cy="60.4" r=".2"/>
<circle cx="70.2" cy="57.1" r=".2"/>
<circle cx="104" cy="56.2" r=".2"/>
<circle cx="107.1" cy="44.6" r=".2"/>
<circle cx="108.1" cy="43.5" r=".2"/>
<circle cx="107.1" cy="41.5" r=".2"/>
<circle cx="101" cy="41" r=".2"/>
<circle cx="81.7" cy="43.3" r=".2"/>
<circle cx="86.6" cy="44" r=".2"/>
<circle cx="71.2" cy="57.1" r=".2"/>
<circle cx="78" cy="50.1" r=".2"/>
<circle cx="79.9" cy="42.1" r=".2"/>
<circle cx="74.1" cy="40.5" r=".2"/>
<circle cx="75.6" cy="44.5" r=".2"/>
<circle cx="58.1" cy="41.5" r=".2"/>
<circle cx="61.4" cy="39.1" r=".2"/>
<circle cx="54.7" cy="43.1" r=".2"/>
<circle cx="51.2" cy="39.7" r=".2"/>
<circle cx="43.3" cy="42.8" r=".2"/>
<circle cx="43.3" cy="38.5" r=".2"/>
<circle cx="62.1" cy="56.6" r=".2"/>
<circle cx="34.7" cy="49" r=".2"/>
<circle cx="33.2" cy="40.2" r=".2"/>
<circle cx="30.1" cy="39.5" r=".2"/>
<circle cx="31.4" cy="43.4" r=".2"/>
<circle cx="122.6" cy="36.9" r=".2"/>
<circle cx="121.8" cy="39.5" r=".2"/>
<circle cx="121.8" cy="54.7" r=".2"/>
<circle cx="121.5" cy="57.4" r=".2"/>
<circle cx="105.5" cy="42" r=".2"/>
<circle cx="103.5" cy="39.3" r=".2"/>
<circle cx="126.4" cy="57.8" r=".2"/>
<circle cx="124.1" cy="55.5" r=".2"/>
<circle cx="115.2" cy="61.3" r=".2"/>
<circle cx="123.3" cy="62.3" r=".2"/>
<circle cx="128.9" cy="66.1" r=".2"/>
<circle cx="130.9" cy="66.1" r=".2"/>
<circle cx="137.6" cy="67.9" r=".2"/>
<circle cx="140.1" cy="67.9" r=".2"/>
<circle cx="105.3" cy="52.7" r=".2"/>
<circle cx="105" cy="59.4" r=".2"/>
<circle cx="103.3" cy="44.8" r=".2"/>
<circle cx="102.8" cy="40" r=".2"/>
<circle cx="122.8" cy="61.5" r=".2"/>
<circle cx="128.9" cy="67.4" r=".2"/>
<circle cx="130.9" cy="67.4" r=".2"/>
<circle cx="137.6" cy="69.4" r=".2"/>
<circle cx="139.3" cy="69.4" r=".2"/>
<circle cx="120.3" cy="50.4" r=".2"/>
<circle cx="125.8" cy="58.6" r=".2"/>
<circle cx="116.2" cy="69.7" r=".2"/>
<circle cx="119.3" cy="52.4" r=".2"/>
<circle cx="106.3" cy="70.2" r=".2"/>
<circle cx="111.4" cy="64.5" r=".2"/>
<circle cx="111.4" cy="59.8" r=".2"/>
<circle cx="111.5" cy="57" r=".2"/>
<circle cx="115.1" cy="46.6" r=".2"/>
<circle cx="119.5" cy="54.9" r=".2"/>
<circle cx="121" cy="53.4" r=".2"/>
<circle cx="120.2" cy="55.6" r=".2"/>
<circle cx="96.5" cy="49.3" r=".2"/>
<circle cx="95.4" cy="49.3" r=".2"/>
<circle cx="53.5" cy="80.5" r=".2"/>
<circle cx="113.2" cy="139.3" r=".4"/>
<circle cx="113.2" cy="117.3" r=".4"/>
<circle cx="115.7" cy="139.3" r=".4"/>
<circle cx="115.7" cy="117.3" r=".4"/>
<circle cx="118.3" cy="139.3" r=".4"/>
<circle cx="118.3" cy="117.3" r=".4"/>
<circle cx="120.8" cy="139.3" r=".4"/>
<circle cx="120.8" cy="117.3" r=".4"/>
<circle cx="123.4" cy="139.3" r=".4"/>
<circle cx="123.4" cy="117.3" r=".4"/>
<circle cx="125.9" cy="139.3" r=".4"/>
<circle cx="125.9" cy="117.3" r=".4"/>
<circle cx="128.4" cy="139.3" r=".4"/>
<circle cx="128.4" cy="117.3" r=".4"/>
<circle cx="131" cy="139.3" r=".4"/>
<circle cx="131" cy="117.3" r=".4"/>
<circle cx="133.5" cy="139.3" r=".4"/>
<circle cx="133.5" cy="117.3" r=".4"/>
<circle cx="136.1" cy="139.3" r=".4"/>
<circle cx="136.1" cy="117.3" r=".4"/>
<circle cx="138.6" cy="139.3" r=".4"/>
<circle cx="138.6" cy="117.3" r=".4"/>
<circle cx="141.1" cy="139.3" r=".4"/>
<circle cx="141.1" cy="117.3" r=".4"/>
<circle cx="143.7" cy="139.3" r=".4"/>
<circle cx="143.7" cy="117.3" r=".4"/>
<circle cx="146.2" cy="139.3" r=".4"/>
<circle cx="146.2" cy="117.3" r=".4"/>
<circle cx="148.8" cy="139.3" r=".4"/>
<circle cx="148.8" cy="117.3" r=".4"/>
<circle cx="151.3" cy="139.3" r=".4"/>
<circle cx="151.3" cy="117.3" r=".4"/>
<circle cx="153.8" cy="139.3" r=".4"/>
<circle cx="153.8" cy="117.3" r=".4"/>
<circle cx="156.4" cy="139.3" r=".4"/>
<circle cx="156.4" cy="117.3" r=".4"/>
<circle cx="158.9" cy="139.3" r=".4"/>
<circle cx="158.9" cy="117.3" r=".4"/>
<circle cx="161.5" cy="139.3" r=".4"/>
<circle cx="161.5" cy="117.3" r=".4"/>
<circle cx="163.6" cy="93.9" r=".45"/>
<circle cx="158.5" cy="93.9" r=".45"/>
<circle cx="153.5" cy="93.9" r=".45"/>
<circle cx="148.4" cy="93.9" r=".45"/>
<circle cx="143.3" cy="93.9" r=".45"/>
<circle cx="138.2" cy="93.9" r=".45"/>
<circle cx="133.1" cy="93.9" r=".45"/>
<circle cx="128.1" cy="93.9" r=".45"/>
<circle cx="123" cy="93.9" r=".45"/>
<circle cx="98.6" cy="77.8" r=".5"/>
<circle cx="98.6" cy="75.3" r=".5"/>
<circle cx="98.6" cy="72.8" r=".5"/>
<circle cx="164.4" cy="162.6" r=".5"/>
<circle cx="161.9" cy="162.6" r=".5"/>
<circle cx="159.4" cy="162.6" r=".5"/>
<circle cx="164" cy="52.2" r=".5"/>
<circle cx="164" cy="49.6" r=".5"/>
<circle cx="28.6" cy="53.9" r=".5"/>
<circle cx="26" cy="53.9" r=".5"/>
<circle cx="151.4" cy="111.8" r=".5"/>
<circle cx="151.4" cy="109.2" r=".5"/>
<circle cx="48.5" cy="72.9" r=".5"/>
<circle cx="48.5" cy="75.4" r=".5"/>
<circle cx="48.5" cy="78" r=".5"/>
<circle cx="52.2" cy="78" r=".5"/>
<circle cx="52.2" cy="75.4" r=".5"/>
<circle cx="52.2" cy="72.9" r=".5"/>
<circle cx="42.2" cy="72.9" r=".5"/>
<circle cx="42.2" cy="75.4" r=".5"/>
<circle cx="42.2" cy="78" r=".5"/>
<circle cx="83.3" cy="72.8" r=".5"/>
<circle cx="83.3" cy="75.3" r=".5"/>
<circle cx="83.3" cy="77.8" r=".5"/>
<circle cx="88.4" cy="77.8" r=".5"/>
<circle cx="88.4" cy="75.3" r=".5"/>
<circle cx="88.4" cy="72.8" r=".5"/>
<circle cx="93.5" cy="72.8" r=".5"/>
<circle cx="93.5" cy="75.3" r=".5"/>
<circle cx="93.5" cy="77.8" r=".5"/>
<circle cx="38.4" cy="72.9" r=".5"/>
<circle cx="38.4" cy="75.4" r=".5"/>
<circle cx="38.4" cy="78" r=".5"/>
<circle cx="139.9" cy="162.6" r=".5"/>
<circle cx="142.4" cy="162.6" r=".5"/>
<circle cx="145" cy="162.6" r=".5"/>
<circle cx="147.5" cy="162.6" r=".5"/>
<circle cx="150" cy="162.6" r=".5"/>
<circle cx="152.6" cy="162.6" r=".5"/>
<circle cx="118.2" cy="104.5" r=".5"/>
<circle cx="118.2" cy="107" r=".5"/>
<circle cx="120.8" cy="104.5" r=".5"/>
<circle cx="120.8" cy="107" r=".5"/>
<circle cx="123.3" cy="104.5" r=".5"/>
<circle cx="123.3" cy="107" r=".5"/>
<circle cx="125.8" cy="104.5" r=".5"/>
<circle cx="125.8" cy="107" r=".5"/>
<circle cx="128.4" cy="104.5" r=".5"/>
<circle cx="128.4" cy="107" r=".5"/>
<circle cx="63.2" cy="60.8" r=".5"/>
<circle cx="65.8" cy="60.8" r=".5"/>
<circle cx="63.2" cy="63.3" r=".5"/>
<circle cx="65.8" cy="63.3" r=".5"/>
<circle cx="63.2" cy="65.9" r=".5"/>
<circle cx="65.8" cy="65.9" r=".5"/>
<circle cx="63.2" cy="68.4" r=".5"/>
<circle cx="65.8" cy="68.4" r=".5"/>
<circle cx="63.2" cy="71" r=".5"/>
<circle cx="65.8" cy="71" r=".5"/>
<circle cx="63.2" cy="73.5" r=".5"/>
<circle cx="65.8" cy="73.5" r=".5"/>
<circle cx="63.2" cy="76" r=".5"/>
<circle cx="65.8" cy="76" r=".5"/>
<circle cx="63.2" cy="78.6" r=".5"/>
<circle cx="65.8" cy="78.6" r=".5"/>
<circle cx="85.2" cy="107.2" r=".5"/>
<circle cx="85.2" cy="109.8" r=".5"/>
<circle cx="87.8" cy="107.2" r=".5"/>
<circle cx="87.8" cy="109.8" r=".5"/>
<circle cx="90.3" cy="107.2" r=".5"/>
<circle cx="90.3" cy="109.8" r=".5"/>
<circle cx="92.8" cy="107.2" r=".5"/>
<circle cx="92.8" cy="109.8" r=".5"/>
<circle cx="95.4" cy="107.2" r=".5"/>
<circle cx="95.4" cy="109.8" r=".5"/>
<circle cx="97.9" cy="107.2" r=".5"/>
<circle cx="97.9" cy="109.8" r=".5"/>
<circle cx="100.5" cy="107.2" r=".5"/>
<circle cx="100.5" cy="109.8" r=".5"/>
<circle cx="103" cy="107.2" r=".5"/>
<circle cx="103" cy="109.8" r=".5"/>
<circle cx="103" cy="30.3" r=".5"/>
<circle cx="103" cy="32.9" r=".5"/>
<circle cx="100.5" cy="30.3" r=".5"/>
<circle cx="100.5" cy="32.9" r=".5"/>
<circle cx="97.9" cy="30.3" r=".5"/>
<circle cx="97.9" cy="32.9" r=".5"/>
<circle cx="95.4" cy="30.3" r=".5"/>
<circle cx="95.4" cy="32.9" r=".5"/>
<circle cx="92.8" cy="30.3" r=".5"/>
<circle cx="92.8" cy="32.9" r=".5"/>
<circle cx="90.3" cy="30.3" r=".5"/>
<circle cx="90.3" cy="32.9" r=".5"/>
<circle cx="87.8" cy="30.3" r=".5"/>
<circle cx="87.8" cy="32.9" r=".5"/>
<circle cx="85.2" cy="30.3" r=".5"/>
<circle cx="85.2" cy="32.9" r=".5"/>
<circle cx="17.4" cy="93.9" r=".45"/>
<circle cx="22.5" cy="93.9" r=".45"/>
<circle cx="27.5" cy="93.9" r=".45"/>
<circle cx="32.6" cy="93.9" r=".45"/>
<circle cx="37.7" cy="93.9" r=".45"/>
<circle cx="42.8" cy="93.9" r=".45"/>
<circle cx="47.9" cy="93.9" r=".45"/>
<circle cx="52.9" cy="93.9" r=".45"/>
<circle cx="58" cy="93.9" r=".45"/>
<circle cx="123" cy="18.3" r=".45"/>
<circle cx="128" cy="18.3" r=".45"/>
<circle cx="133.1" cy="18.3" r=".45"/>
<circle cx="138.2" cy="18.3" r=".45"/>
<circle cx="143.3" cy="18.3" r=".45"/>
<circle cx="148.4" cy="18.3" r=".45"/>
<circle cx="153.4" cy="18.3" r=".45"/>
<circle cx="158.5" cy="18.3" r=".45"/>
<circle cx="163.6" cy="18.3" r=".45"/>
<circle cx="110.8" cy="18.3" r=".45"/>
<circle cx="105.7" cy="18.3" r=".45"/>
<circle cx="100.6" cy="18.3" r=".45"/>
<circle cx="95.6" cy="18.3" r=".45"/>
<circle cx="90.5" cy="18.3" r=".45"/>
<circle cx="85.4" cy="18.3" r=".45"/>
<circle cx="80.3" cy="18.3" r=".45"/>
<circle cx="75.2" cy="18.3" r=".45"/>
<circle cx="70.2" cy="18.3" r=".45"/>
<circle cx="70.2" cy="93.9" r=".45"/>
<circle cx="75.3" cy="93.9" r=".45"/>
<circle cx="80.3" cy="93.9" r=".45"/>
<circle cx="85.4" cy="93.9" r=".45"/>
<circle cx="90.5" cy="93.9" r=".45"/>
<circle cx="95.6" cy="93.9" r=".45"/>
<circle cx="100.7" cy="93.9" r=".45"/>
<circle cx="105.7" cy="93.9" r=".45"/>
<circle cx="110.8" cy="93.9" r=".45"/>
<circle cx="17.4" cy="18.3" r=".45"/>
<circle cx="22.4" cy="18.3" r=".45"/>
<circle cx="27.5" cy="18.3" r=".45"/>
<circle cx="32.6" cy="18.3" r=".45"/>
<circle cx="37.7" cy="18.3" r=".45"/>
<circle cx="42.8" cy="18.3" r=".45"/>
<circle cx="47.8" cy="18.3" r=".45"/>
<circle cx="52.9" cy="18.3" r=".45"/>
<circle cx="58" cy="18.3" r=".45"/>
<circle cx="18.2" cy="83.3" r=".5"/>
<circle cx="20.8" cy="83.3" r=".5"/>
<circle cx="23.3" cy="83.3" r=".5"/>
<circle cx="145.7" cy="50.2" r=".4"/>
<circle cx="145.7" cy="52.7" r=".4"/>
<circle cx="31.7" cy="72.2" r=".4"/>
<circle cx="29.2" cy="72.2" r=".4"/>
</g>
</svg>
